VERSION 5.8 ;
DIVIDERCHAR "/" ;
BUSBITCHARS "[]" ;
UNITS
  DATABASE MICRONS 2000 ;
END UNITS

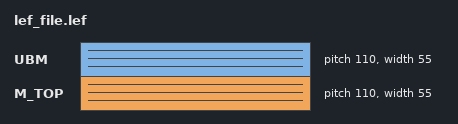
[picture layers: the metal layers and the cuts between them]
LAYER M_TOP
  TYPE ROUTING ;
  DIRECTION HORIZONTAL ;
  PITCH 110.000 ;
  WIDTH 55.000 ;
  SPACING 0.000 ;
  RESISTANCE RPERSQ 0.01 ;
  CAPACITANCE CPERSQDIST 0.001 ;
END M_TOP

LAYER UBM
  TYPE ROUTING ;
  DIRECTION HORIZONTAL ;
  PITCH 110.000 ;
  WIDTH 55.000 ;
  SPACING 0.000 ;
  RESISTANCE RPERSQ 0.01 ;
  CAPACITANCE CPERSQDIST 0.001 ;
END UBM

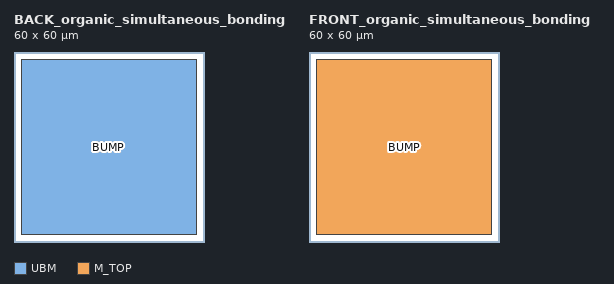
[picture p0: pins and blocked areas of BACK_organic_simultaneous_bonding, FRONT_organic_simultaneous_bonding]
MACRO BACK_organic_simultaneous_bonding
  CLASS COVER BUMP ;
  FOREIGN organic_simultaneous_bonding 0 0 ;
  ORIGIN 0 0 ;
  SIZE 60.000 BY 60.000 ;
  PIN BUMP
    DIRECTION INOUT ;
    USE SIGNAL ;
    PORT
      LAYER UBM ;
        RECT 2.500 2.500 57.500 57.500 ;
    END
  END BUMP
END BACK_organic_simultaneous_bonding

MACRO FRONT_organic_simultaneous_bonding
  CLASS COVER BUMP ;
  FOREIGN organic_simultaneous_bonding 0 0 ;
  ORIGIN 0 0 ;
  SIZE 60.000 BY 60.000 ;
  PIN BUMP
    DIRECTION INOUT ;
    USE SIGNAL ;
    PORT
      LAYER M_TOP ;
        RECT 2.500 2.500 57.500 57.500 ;
    END
  END BUMP
END FRONT_organic_simultaneous_bonding

